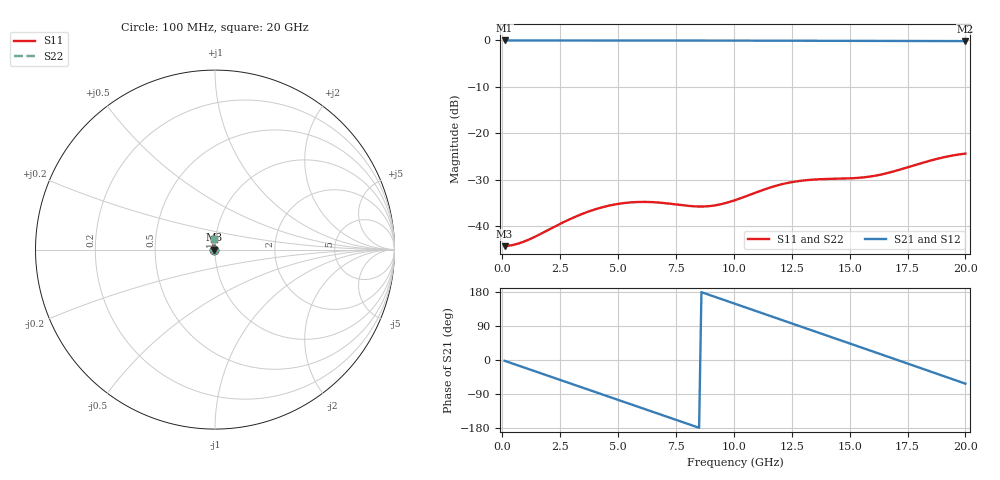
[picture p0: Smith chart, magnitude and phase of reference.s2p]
! circuitRF F0 spike reference -- case B, openEMS, dielectric loss as kappa fitted at 10 GHz, dw 25 um, 73000 steps (2.0 ns)
! openEMS probes -> S by postproc.py (own time column per probe); port 1 excited only;
! S22 = S11 and S12 = S21 by the 180-degree rotational symmetry (not a second run)
# GHz S RI R 50
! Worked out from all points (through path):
!   200 points, 100 MHz to 20 GHz, reference 50 ohm
!   highest |S21| = -0.05 dB at 100 MHz (marker M1); lowest = -0.2 dB at 20 GHz (marker M2)
!   group delay of S21, straight-line fit = 58.7 ps
!   lowest |S11| = -44.3 dB at 100 MHz (marker M3), VSWR 1.01, Z = 49.4 + j0.0202 ohm
!   |S11| at or under -10 dB: start of sweep to end of sweep
!   |S22| runs from -44.3 to -24.4 dB; largest |S21 - S12| = 0
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0.1  -0.00612 0.000204  0.9932 -0.0365  0.9932 -0.0365  -0.00612 0.000204
0.9  -0.00649 0.00205  0.9402 -0.3222  0.9402 -0.3222  -0.00649 0.00205
1.7  -0.00713 0.00443  0.8067 -0.5804  0.8067 -0.5804  -0.00713 0.00443
2.6  -0.00753 0.00794  0.5748 -0.8106  0.5748 -0.8106  -0.00753 0.00794
3.5  -0.00687 0.0119  0.2809 -0.9531  0.2809 -0.9531  -0.00687 0.0119
4.3  -0.00518 0.0151  -0.00707 -0.9934  -0.00707 -0.9934  -0.00518 0.0151
5.1  -0.00276 0.0174  -0.2944 -0.9486  -0.2944 -0.9486  -0.00276 0.0174
5.9  -0.000274 0.0183  -0.5564 -0.8224  -0.5564 -0.8224  -0.000274 0.0183
6.8  0.00162 0.0179  -0.7931 -0.5968  -0.7931 -0.5968  0.00162 0.0179
7.7  0.00181 0.0169  -0.9436 -0.3064  -0.9436 -0.3064  0.00181 0.0169
8.5  0.000475 0.0163  -0.9913 -0.0193  -0.9913 -0.0193  0.000475 0.0163
9.3  -0.00178 0.0169  -0.9536 0.2692  -0.9536 0.2692  -0.00178 0.0169
10.1  -0.00421 0.0188  -0.8336 0.5343  -0.8336 0.5343  -0.00421 0.0188
11.8  -0.00664 0.0264  -0.3608 0.9192  -0.3608 0.9192  -0.00664 0.0264
12.6  -0.0056 0.0296  -0.0781 0.9832  -0.0781 0.9832  -0.0056 0.0296
13.4  -0.00423 0.0315  0.2109 0.9624  0.2109 0.9624  -0.00423 0.0315
14.3  -0.00354 0.0322  0.5127 0.8401  0.5127 0.8401  -0.00354 0.0322
15.2  -0.00463 0.0326  0.7581 0.6261  0.7581 0.6261  -0.00463 0.0326
16.7  -0.00972 0.0365  0.9727 0.1323  0.9727 0.1323  -0.00972 0.0365
17.5  -0.0123 0.0413  0.968 -0.1576  0.968 -0.1576  -0.0123 0.0413
18.3  -0.0131 0.0476  0.8788 -0.4335  0.8788 -0.4335  -0.0131 0.0476
20  -0.00693 0.0602  0.4522 -0.8673  0.4522 -0.8673  -0.00693 0.0602
